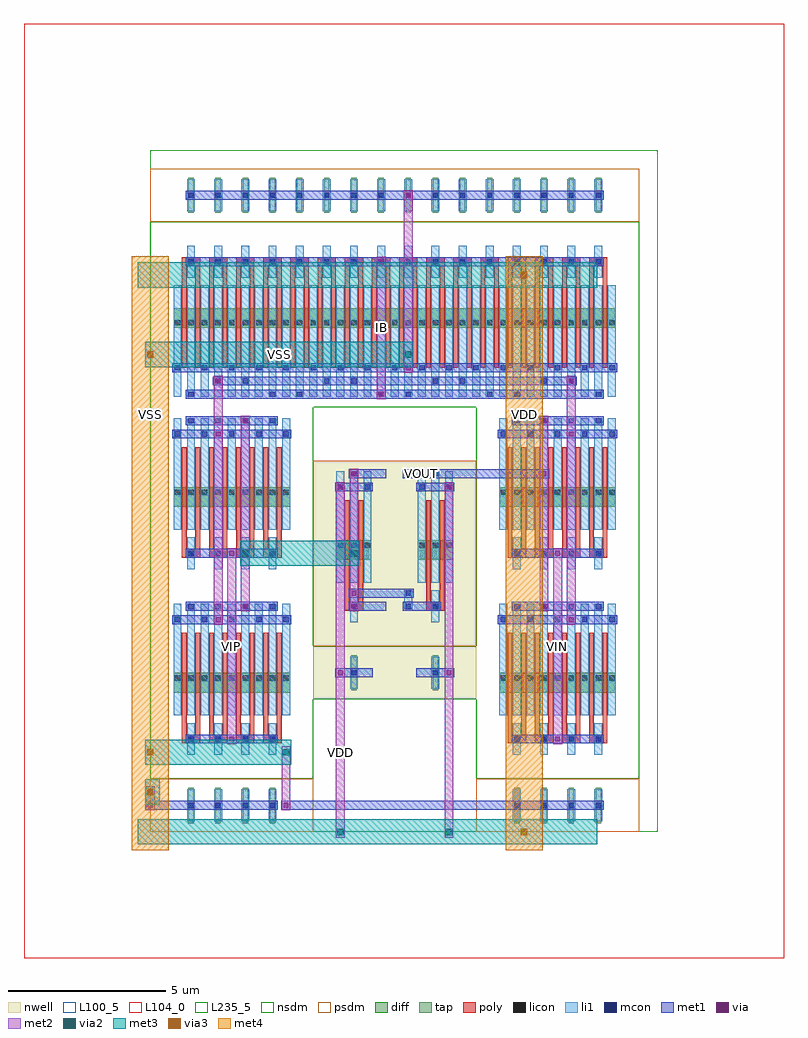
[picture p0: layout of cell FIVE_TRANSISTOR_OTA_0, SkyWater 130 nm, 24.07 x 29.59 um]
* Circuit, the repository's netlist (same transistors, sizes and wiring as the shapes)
* NGSPICE file created from FIVE_TRANSISTOR_OTA_0.ext - technology: sky130A

.subckt DCL_PMOS_S_8161858_X1_Y1_1774869053 a_200_252# w_0_0#
X0 a_200_252# a_200_252# w_0_0# w_0_0# sky130_fd_pr__pfet_01v8 ad=0.0882 pd=0.91 as=0.16695 ps=1.79 w=0.63 l=0.15 M=2
.ends

.subckt SCM_NMOS_1433580_X8_Y1_1774869056 a_147_504# a_200_252# a_402_504#
X0 a_147_504# a_200_252# a_402_504# a_147_504# sky130_fd_pr__nfet_01v8 ad=0.0882 pd=0.91 as=0.0882 ps=0.91 w=0.63 l=0.15 M=16
X1 a_200_252# a_200_252# a_147_504# a_147_504# sky130_fd_pr__nfet_01v8 ad=0.0882 pd=0.91 as=0.16695 ps=1.79 w=0.63 l=0.15 M=16
.ends

.subckt PMOS_S_96204883_X1_Y1_1774869055 a_200_252# w_0_0# a_230_504#
X0 a_230_504# a_200_252# w_0_0# w_0_0# sky130_fd_pr__pfet_01v8 ad=0.0882 pd=0.91 as=0.16695 ps=1.79 w=0.63 l=0.15 M=2
.ends

.subckt NMOS_4T_7455775_X4_Y2_1774869054 a_147_504# a_200_252# a_230_504# a_241_2408#
X0 a_230_504# a_200_252# a_147_504# a_241_2408# sky130_fd_pr__nfet_01v8 ad=0.0882 pd=0.91 as=0.16695 ps=1.79 w=0.63 l=0.15 M=16
.ends

.subckt FIVE_TRANSISTOR_OTA_0 IB VOUT VIP VIN VSS VDD
XDCL_PMOS_S_8161858_X1_Y1_1774869053_0 m2_574_1727# VDD DCL_PMOS_S_8161858_X1_Y1_1774869053
XSCM_NMOS_1433580_X8_Y1_1774869056_0 VSS IB m1_398_2828# SCM_NMOS_1433580_X8_Y1_1774869056
XPMOS_S_96204883_X1_Y1_1774869055_0 m2_574_1727# VDD VOUT PMOS_S_96204883_X1_Y1_1774869055
XNMOS_4T_7455775_X4_Y2_1774869054_0 m1_398_2828# VIN VOUT VSS NMOS_4T_7455775_X4_Y2_1774869054
XNMOS_4T_7455775_X4_Y2_1774869054_1 m1_398_2828# VIP m2_574_1727# VSS NMOS_4T_7455775_X4_Y2_1774869054
.ends

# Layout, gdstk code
from math import pi, radians
import gdstk
lib = gdstk.Library(unit=1e-6, precision=1e-09)
def R(c, l, rs):  # rectangles x0, y0, x1, y1
    for r in rs: c.add(gdstk.rectangle(r[:2], r[2:], *l))
def A(c, l, x, y, w, h, nx, ny, dx, dy):  # array of equal rectangles
    R(c, l, [(x+i*dx, y+j*dy, x+i*dx+w, y+j*dy+h) for i in range(nx) for j in range(ny)])
def P(c, l, *ps):  # polygons
    for p in ps: c.add(gdstk.Polygon(p, *l))
nwell = (64, 20)
diff = (65, 20)
tap = (65, 44)
poly = (66, 20)
licon = (66, 44)
li1 = (67, 20)
mcon = (67, 44)
met1 = (68, 20)
via = (68, 44)
met2 = (69, 20)
via2 = (69, 44)
met3 = (70, 20)
via3 = (70, 44)
met4 = (71, 20)
nsdm = (93, 44)
psdm = (94, 20)
L100_5 = (100, 5)
L104_0 = (104, 0)
L235_5 = (235, 5)

scm_nmos_1433580_x8_y1_1 = lib.new_cell('SCM_NMOS_1433580_X8_Y1_1774869056')
R(scm_nmos_1433580_x8_y1_1, diff, [(0.735,2.52,14.745,3.15)])
A(scm_nmos_1433580_x8_y1_1, tap, 1.205, 6.16, 0.17, 1.12, 16, 1, 0.86, 0)
A(scm_nmos_1433580_x8_y1_1, poly, 1, 1.26, 0.15, 3.36, 32, 1, 0.43, 0)
A(scm_nmos_1433580_x8_y1_1, poly, 1, 4.485, 0.58, 0.27, 16, 1, 0.86, 0)
A(scm_nmos_1433580_x8_y1_1, licon, 0.775, 2.6, 0.17, 0.17, 3, 1, 0.43, 0)
A(scm_nmos_1433580_x8_y1_1, licon, 1.635, 2.6, 0.17, 0.17, 3, 1, 0.43, 0)
A(scm_nmos_1433580_x8_y1_1, licon, 2.495, 2.6, 0.17, 0.17, 3, 1, 0.43, 0)
A(scm_nmos_1433580_x8_y1_1, licon, 3.355, 2.6, 0.17, 0.17, 3, 1, 0.43, 0)
A(scm_nmos_1433580_x8_y1_1, licon, 4.215, 2.6, 0.17, 0.17, 3, 1, 0.43, 0)
A(scm_nmos_1433580_x8_y1_1, licon, 5.075, 2.6, 0.17, 0.17, 3, 1, 0.43, 0)
A(scm_nmos_1433580_x8_y1_1, licon, 5.935, 2.6, 0.17, 0.17, 3, 1, 0.43, 0)
A(scm_nmos_1433580_x8_y1_1, licon, 6.795, 2.6, 0.17, 0.17, 3, 1, 0.43, 0)
A(scm_nmos_1433580_x8_y1_1, licon, 7.655, 2.6, 0.17, 0.17, 3, 1, 0.43, 0)
A(scm_nmos_1433580_x8_y1_1, licon, 8.515, 2.6, 0.17, 0.17, 3, 1, 0.43, 0)
A(scm_nmos_1433580_x8_y1_1, licon, 9.375, 2.6, 0.17, 0.17, 3, 1, 0.43, 0)
A(scm_nmos_1433580_x8_y1_1, licon, 10.235, 2.6, 0.17, 0.17, 3, 1, 0.43, 0)
A(scm_nmos_1433580_x8_y1_1, licon, 11.095, 2.6, 0.17, 0.17, 3, 1, 0.43, 0)
A(scm_nmos_1433580_x8_y1_1, licon, 11.955, 2.6, 0.17, 0.17, 3, 1, 0.43, 0)
A(scm_nmos_1433580_x8_y1_1, licon, 12.815, 2.6, 0.17, 0.17, 3, 1, 0.43, 0)
A(scm_nmos_1433580_x8_y1_1, licon, 13.675, 2.6, 0.17, 0.17, 3, 1, 0.43, 0)
A(scm_nmos_1433580_x8_y1_1, licon, 1.205, 4.535, 0.17, 0.17, 16, 2, 0.86, 2.1)
A(scm_nmos_1433580_x8_y1_1, li1, 0.735, 0.335, 0.25, 3.53, 33, 1, 0.43, 0)
A(scm_nmos_1433580_x8_y1_1, li1, 1.165, 4.115, 0.25, 1.01, 16, 2, 0.86, 2.1)
A(scm_nmos_1433580_x8_y1_1, mcon, 0.775, 1.175, 0.17, 0.17, 17, 1, 0.86, 0)
A(scm_nmos_1433580_x8_y1_1, mcon, 1.205, 4.535, 0.17, 0.17, 16, 2, 0.86, 2.1)
R(scm_nmos_1433580_x8_y1_1, mcon, [(1.205,0.335,1.375,0.505), (3.785,0.335,3.955,0.505), (4.645,0.335,4.815,0.505), (7.225,0.335,7.395,0.505), (8.085,0.335,8.255,0.505), (10.665,0.335,10.835,0.505), (11.525,0.335,11.695,0.505), (14.105,0.335,14.275,0.505), (2.065,0.755,2.235,0.925), (2.925,0.755,3.095,0.925), (5.505,0.755,5.675,0.925), (6.365,0.755,6.535,0.925), (8.945,0.755,9.115,0.925), (9.805,0.755,9.975,0.925), (12.385,0.755,12.555,0.925), (13.245,0.755,13.415,0.925)])
R(scm_nmos_1433580_x8_y1_1, met1, [(1.12,0.28,14.36,0.56), (1.98,0.7,13.5,0.98), (0.69,1.12,14.79,1.4), (1.12,4.48,14.36,4.76), (1.12,6.58,14.36,6.86)])
R(scm_nmos_1433580_x8_y1_1, via, [(7.235,0.345,7.385,0.495), (8.095,1.185,8.245,1.335), (7.235,4.545,7.385,4.695), (8.095,6.645,8.245,6.795)])
R(scm_nmos_1433580_x8_y1_1, met2, [(7.17,0.26,7.45,4.78), (8.03,1.1,8.31,6.88)])
R(scm_nmos_1433580_x8_y1_1, nsdm, [(0,0,15.48,5.88)])
R(scm_nmos_1433580_x8_y1_1, psdm, [(0,5.88,15.48,7.56)])
R(scm_nmos_1433580_x8_y1_1, L100_5, [(0,0,15.48,7.56)])

dcl_pmos_s_8161858_x1_y1 = lib.new_cell('DCL_PMOS_S_8161858_X1_Y1_1774869053')
R(dcl_pmos_s_8161858_x1_y1, nwell, [(0,0,2.58,7.56)])
R(dcl_pmos_s_8161858_x1_y1, diff, [(0.735,2.52,1.845,3.15)])
R(dcl_pmos_s_8161858_x1_y1, tap, [(1.205,6.16,1.375,7.28)])
R(dcl_pmos_s_8161858_x1_y1, poly, [(1,1.26,1.15,4.62), (1.43,1.26,1.58,4.62), (1,4.485,1.58,4.755)])
A(dcl_pmos_s_8161858_x1_y1, licon, 0.775, 2.6, 0.17, 0.17, 3, 1, 0.43, 0)
R(dcl_pmos_s_8161858_x1_y1, licon, [(1.205,4.535,1.375,4.705), (1.205,6.635,1.375,6.805)])
A(dcl_pmos_s_8161858_x1_y1, li1, 0.735, 0.335, 0.25, 3.53, 3, 1, 0.43, 0)
R(dcl_pmos_s_8161858_x1_y1, li1, [(1.165,4.115,1.415,5.125), (1.165,6.215,1.415,7.225)])
R(dcl_pmos_s_8161858_x1_y1, mcon, [(1.205,0.335,1.375,0.505), (0.775,0.755,0.945,0.925), (1.635,0.755,1.805,0.925), (1.205,4.535,1.375,4.705), (1.205,6.635,1.375,6.805)])
R(dcl_pmos_s_8161858_x1_y1, met1, [(0.26,0.28,1.46,0.56), (0.69,0.7,1.89,0.98), (0.26,4.48,1.46,4.76), (0.69,6.58,1.89,6.86)])
R(dcl_pmos_s_8161858_x1_y1, via, [(1.215,0.345,1.365,0.495), (1.645,0.765,1.795,0.915), (1.215,4.545,1.365,4.695), (1.645,6.645,1.795,6.795)])
R(dcl_pmos_s_8161858_x1_y1, met2, [(1.15,0.26,1.43,4.78), (1.58,0.68,1.86,6.88)])
R(dcl_pmos_s_8161858_x1_y1, nsdm, [(0,5.88,2.58,7.56)])
R(dcl_pmos_s_8161858_x1_y1, psdm, [(0,0,2.58,5.88)])
R(dcl_pmos_s_8161858_x1_y1, L100_5, [(0,0,2.58,7.56)])

pmos_s_96204883_x1_y1_17 = lib.new_cell('PMOS_S_96204883_X1_Y1_1774869055')
R(pmos_s_96204883_x1_y1_17, nwell, [(0,0,2.58,7.56)])
R(pmos_s_96204883_x1_y1_17, diff, [(0.735,2.52,1.845,3.15)])
R(pmos_s_96204883_x1_y1_17, tap, [(1.205,6.16,1.375,7.28)])
R(pmos_s_96204883_x1_y1_17, poly, [(1,1.26,1.15,4.62), (1.43,1.26,1.58,4.62), (1,4.485,1.58,4.755)])
A(pmos_s_96204883_x1_y1_17, licon, 0.775, 2.6, 0.17, 0.17, 3, 1, 0.43, 0)
R(pmos_s_96204883_x1_y1_17, licon, [(1.205,4.535,1.375,4.705), (1.205,6.635,1.375,6.805)])
A(pmos_s_96204883_x1_y1_17, li1, 0.735, 0.335, 0.25, 3.53, 3, 1, 0.43, 0)
R(pmos_s_96204883_x1_y1_17, li1, [(1.165,4.115,1.415,5.125), (1.165,6.215,1.415,7.225)])
R(pmos_s_96204883_x1_y1_17, mcon, [(1.205,0.335,1.375,0.505), (0.775,0.755,0.945,0.925), (1.635,0.755,1.805,0.925), (1.205,4.535,1.375,4.705), (1.205,6.635,1.375,6.805)])
R(pmos_s_96204883_x1_y1_17, met1, [(0.26,0.28,1.46,0.56), (0.69,0.7,1.89,0.98), (0.26,4.48,1.46,4.76), (0.69,6.58,1.89,6.86)])
R(pmos_s_96204883_x1_y1_17, via, [(1.645,0.765,1.795,0.915), (1.645,6.645,1.795,6.795)])
R(pmos_s_96204883_x1_y1_17, met2, [(1.58,0.68,1.86,6.88)])
R(pmos_s_96204883_x1_y1_17, nsdm, [(0,5.88,2.58,7.56)])
R(pmos_s_96204883_x1_y1_17, psdm, [(0,0,2.58,5.88)])
R(pmos_s_96204883_x1_y1_17, L100_5, [(0,0,2.58,7.56)])

nmos_4t_7455775_x4_y2_17 = lib.new_cell('NMOS_4T_7455775_X4_Y2_1774869054')
R(nmos_4t_7455775_x4_y2_17, diff, [(0.735,2.52,4.425,3.15), (0.735,8.4,4.425,9.03)])
A(nmos_4t_7455775_x4_y2_17, tap, 1.205, 12.04, 0.17, 1.12, 4, 1, 0.86, 0)
A(nmos_4t_7455775_x4_y2_17, poly, 1, 1.26, 0.15, 3.36, 8, 2, 0.43, 5.88)
A(nmos_4t_7455775_x4_y2_17, poly, 1, 4.485, 0.58, 0.27, 4, 2, 0.86, 5.88)
A(nmos_4t_7455775_x4_y2_17, licon, 0.775, 2.6, 0.17, 0.17, 3, 2, 0.43, 5.88)
A(nmos_4t_7455775_x4_y2_17, licon, 1.635, 2.6, 0.17, 0.17, 3, 2, 0.43, 5.88)
A(nmos_4t_7455775_x4_y2_17, licon, 2.495, 2.6, 0.17, 0.17, 3, 2, 0.43, 5.88)
A(nmos_4t_7455775_x4_y2_17, licon, 3.355, 2.6, 0.17, 0.17, 3, 2, 0.43, 5.88)
A(nmos_4t_7455775_x4_y2_17, licon, 1.205, 4.535, 0.17, 0.17, 4, 2, 0.86, 5.88)
R(nmos_4t_7455775_x4_y2_17, licon, [(1.205,12.515,1.375,12.685), (1.205,12.515,1.375,12.685), (2.065,12.515,2.235,12.685), (2.065,12.515,2.235,12.685), (2.925,12.515,3.095,12.685), (2.925,12.515,3.095,12.685), (3.785,12.515,3.955,12.685), (3.785,12.515,3.955,12.685)])
A(nmos_4t_7455775_x4_y2_17, li1, 0.735, 0.335, 0.25, 3.53, 9, 2, 0.43, 5.88)
A(nmos_4t_7455775_x4_y2_17, li1, 1.165, 4.115, 0.25, 1.01, 4, 2, 0.86, 5.88)
A(nmos_4t_7455775_x4_y2_17, li1, 1.165, 12.095, 0.25, 1.01, 4, 1, 0.86, 0)
A(nmos_4t_7455775_x4_y2_17, mcon, 1.205, 0.335, 0.17, 0.17, 4, 2, 0.86, 4.2)
A(nmos_4t_7455775_x4_y2_17, mcon, 0.775, 0.755, 0.17, 0.17, 5, 2, 0.86, 5.88)
A(nmos_4t_7455775_x4_y2_17, mcon, 1.205, 6.215, 0.17, 0.17, 4, 2, 0.86, 4.2)
A(nmos_4t_7455775_x4_y2_17, mcon, 1.205, 12.515, 0.17, 0.17, 4, 1, 0.86, 0)
R(nmos_4t_7455775_x4_y2_17, met1, [(1.12,0.28,4.04,0.56), (0.69,0.7,4.47,0.98), (1.12,4.48,4.04,4.76), (1.12,6.16,4.04,6.44), (0.69,6.58,4.47,6.86), (1.12,10.36,4.04,10.64), (1.12,12.46,4.04,12.74)])
R(nmos_4t_7455775_x4_y2_17, via, [(2.075,0.345,2.225,0.495), (2.935,0.765,3.085,0.915), (2.505,4.545,2.655,4.695), (2.075,6.225,2.225,6.375), (2.935,6.645,3.085,6.795), (2.505,10.425,2.655,10.575)])
R(nmos_4t_7455775_x4_y2_17, met2, [(2.01,0.26,2.29,6.46), (2.87,0.68,3.15,6.88), (2.44,4.46,2.72,10.66)])
R(nmos_4t_7455775_x4_y2_17, nsdm, [(0,0,5.16,11.76)])
R(nmos_4t_7455775_x4_y2_17, psdm, [(0,11.76,5.16,13.44)])
R(nmos_4t_7455775_x4_y2_17, L100_5, [(0,0,5.16,13.44)])

five_transistor_ota_0 = lib.new_cell('FIVE_TRANSISTOR_OTA_0')
R(five_transistor_ota_0, li1, [(8.045,7.055,8.295,7.225), (8.045,7.055,8.295,7.225), (8.045,7.14,8.295,7.56), (8.045,7.475,8.295,7.645), (8.045,7.475,8.295,7.645)])
R(five_transistor_ota_0, mcon, [(8.085,7.055,8.255,7.225), (8.085,7.055,8.255,7.225), (8.085,7.475,8.255,7.645), (8.085,7.475,8.255,7.645)])
R(five_transistor_ota_0, met1, [(-0.16,0.7,0.16,0.98), (-0.16,0.7,0.16,0.98), (-0.16,0.7,0.16,0.98), (0,0.7,1.29,0.98), (4.14,0.7,4.46,0.98), (4.14,0.7,4.46,0.98), (4.3,0.7,11.61,0.98), (8,7,8.34,7.28), (8,7,8.34,7.28), (6.29,7.42,6.61,7.7), (6.29,7.42,6.61,7.7), (6.45,7.42,8.17,7.7), (8,7.42,8.34,7.7), (8,7.42,8.34,7.7), (9.03,11.2,12.47,11.48), (12.31,11.2,12.63,11.48), (12.31,11.2,12.63,11.48), (1.99,14.14,2.31,14.42), (1.99,14.14,2.31,14.42), (1.99,14.14,2.31,14.42), (1.99,14.14,2.31,14.42), (13.17,14.14,13.49,14.42), (13.17,14.14,13.49,14.42)])
P(five_transistor_ota_0, met1, [(0,0),(0,0),(0,0),(0,0)],
  [(0,0),(0,0),(0,0),(0,0)],
  [(0,0),(0,0),(0,0),(0,0)],
  [(0,0),(0,0),(0,0),(0,0)],
  [(0,0),(0,0),(0,0),(0,0)],
  [(0,0),(0,0),(0,0),(0,0)])
R(five_transistor_ota_0, via, [(-0.075,0.765,0.075,0.915), (-0.075,0.765,0.075,0.915), (-0.075,0.765,0.075,0.915), (4.225,0.765,4.375,0.915), (4.225,0.765,4.375,0.915), (6.375,7.485,6.525,7.635), (6.375,7.485,6.525,7.635), (12.395,11.265,12.545,11.415), (12.395,11.265,12.545,11.415), (2.075,14.205,2.225,14.355), (2.075,14.205,2.225,14.355), (2.075,14.205,2.225,14.355), (2.075,14.205,2.225,14.355), (13.255,14.205,13.405,14.355), (13.255,14.205,13.405,14.355)])
R(five_transistor_ota_0, met2, [(5.88,-0.185,6.16,0.185), (5.88,-0.185,6.16,0.185), (5.88,-0.185,6.16,0.185), (9.32,-0.185,9.6,0.185), (9.32,-0.185,9.6,0.185), (5.88,0,6.16,5.04), (9.32,0,9.6,5.04), (-0.14,0.68,0.14,1), (-0.14,0.68,0.14,1), (-0.14,0.68,0.14,1), (4.16,0.68,4.44,1), (4.16,0.68,4.44,1), (-0.14,0.84,0.14,1.26), (4.16,0.84,4.44,2.52), (-0.14,1.075,0.14,1.445), (-0.14,1.075,0.14,1.445), (-0.14,1.075,0.14,1.445), (4.16,2.335,4.44,2.705), (4.16,2.335,4.44,2.705), (6.31,7.4,6.59,7.72), (6.31,7.4,6.59,7.72), (2.87,8.635,3.15,9.005), (2.87,8.635,3.15,9.005), (2.87,8.635,3.15,9.005), (2.87,8.635,3.15,9.005), (6.31,8.635,6.59,9.005), (6.31,8.635,6.59,9.005), (6.31,8.635,6.59,9.005), (6.31,8.635,6.59,9.005), (12.33,11.18,12.61,11.5), (12.33,11.18,12.61,11.5), (2.01,12.6,2.29,14.28), (13.19,12.6,13.47,14.28), (2.01,14.12,2.29,14.44), (2.01,14.12,2.29,14.44), (2.01,14.12,2.29,14.44), (2.01,14.12,2.29,14.44), (13.19,14.12,13.47,14.44), (13.19,14.12,13.47,14.44), (8.03,14.935,8.31,15.305), (8.03,14.935,8.31,15.305), (8.03,14.935,8.31,15.305), (8.03,14.935,8.31,15.305)])
P(five_transistor_ota_0, met2, [(0,0),(0,0),(0,0),(0,0)],
  [(0,0),(0,0),(0,0),(0,0)],
  [(0,0),(0,0),(0,0),(0,0)],
  [(0,0),(0,0),(0,0),(0,0)],
  [(0,0),(0,0),(0,0),(0,0)],
  [(0,0),(0,0),(0,0),(0,0)],
  [(0,0),(0,0),(0,0),(0,0)],
  [(0,0),(0,0),(0,0),(0,0)],
  [(0,0),(0,0),(0,0),(0,0)],
  [(0,0),(0,0),(0,0),(0,0)],
  [(0,0),(0,0),(0,0),(0,0)],
  [(0,0),(0,0),(0,0),(0,0)],
  [(0,0),(0,0),(0,0),(0,0)],
  [(0,0),(0,0),(0,0),(0,0)])
R(five_transistor_ota_0, via2, [(5.92,-0.1,6.12,0.1), (5.92,-0.1,6.12,0.1), (5.92,-0.1,6.12,0.1), (9.36,-0.1,9.56,0.1), (9.36,-0.1,9.56,0.1), (-0.1,1.16,0.1,1.36), (-0.1,1.16,0.1,1.36), (-0.1,1.16,0.1,1.36), (4.2,2.42,4.4,2.62), (4.2,2.42,4.4,2.62), (2.91,8.72,3.11,8.92), (2.91,8.72,3.11,8.92), (2.91,8.72,3.11,8.92), (2.91,8.72,3.11,8.92), (6.35,8.72,6.55,8.92), (6.35,8.72,6.55,8.92), (6.35,8.72,6.55,8.92), (6.35,8.72,6.55,8.92), (8.07,15.02,8.27,15.22), (8.07,15.02,8.27,15.22), (8.07,15.02,8.27,15.22), (8.07,15.02,8.27,15.22)])
A(five_transistor_ota_0, met3, -0.4, -0.4, 4.24, 0.8, 3, 2, 3.44, 17.64)
R(five_transistor_ota_0, met3, [(5.855,-0.4,6.185,0.4), (5.855,-0.4,6.185,0.4), (5.855,-0.4,6.185,0.4), (9.295,-0.4,9.625,0.4), (9.295,-0.4,9.625,0.4), (9.92,-0.4,12.24,0.4), (11.44,-0.4,14.16,0.4), (11.675,-0.4,12.005,0.4), (-0.165,0.86,0.165,1.66), (-0.165,0.86,0.165,1.66), (-0.165,0.86,0.165,1.66), (-0.165,0.86,0.165,1.66), (-0.165,0.86,0.165,1.66), (-0.165,0.86,0.165,1.66), (0,0.86,0.3,1.66), (-0.165,2.12,0.165,2.92), (-0.165,2.12,0.165,2.92), (0,2.12,4.3,2.92), (4.135,2.12,4.465,2.92), (4.135,2.12,4.465,2.92), (2.845,8.42,3.175,9.22), (2.845,8.42,3.175,9.22), (2.845,8.42,3.175,9.22), (2.845,8.42,3.175,9.22), (3.01,8.42,6.45,9.22), (6.285,8.42,6.615,9.22), (6.285,8.42,6.615,9.22), (6.285,8.42,6.615,9.22), (6.285,8.42,6.615,9.22), (-0.165,14.72,0.165,15.52), (-0.165,14.72,0.165,15.52), (-0.165,14.72,0.165,15.52), (-0.165,14.72,0.165,15.52), (0,14.72,8.17,15.52), (8.005,14.72,8.335,15.52), (8.005,14.72,8.335,15.52), (8.005,14.72,8.335,15.52), (8.005,14.72,8.335,15.52), (9.92,17.24,12.24,18.04), (11.44,17.24,14.16,18.04), (11.675,17.24,12.005,18.04)])
R(five_transistor_ota_0, via3, [(11.74,-0.1,11.94,0.1), (-0.1,1.16,0.1,1.36), (-0.1,1.16,0.1,1.36), (-0.1,1.16,0.1,1.36), (-0.1,2.42,0.1,2.62), (-0.1,2.42,0.1,2.62), (-0.1,15.02,0.1,15.22), (-0.1,15.02,0.1,15.22), (-0.1,15.02,0.1,15.22), (-0.1,15.02,0.1,15.22), (11.74,17.54,11.94,17.74)])
R(five_transistor_ota_0, met4, [(-0.59,-0.59,0.59,9.41), (11.25,-0.59,12.43,9.41), (11.25,-0.165,12.43,0.165), (-0.59,1.095,0.59,1.425), (-0.59,1.095,0.59,1.425), (-0.59,1.095,0.59,1.425), (-0.59,2.355,0.59,2.685), (-0.59,2.355,0.59,2.685), (-0.59,8.23,0.59,18.23), (11.25,8.23,12.43,18.23), (-0.59,14.955,0.59,15.285), (-0.59,14.955,0.59,15.285), (-0.59,14.955,0.59,15.285), (-0.59,14.955,0.59,15.285), (11.25,17.475,12.43,17.805)])
R(five_transistor_ota_0, L104_0, [(-4,-4,20.07,25.59)])
R(five_transistor_ota_0, L235_5, [(0,0,16.07,21.59)])
five_transistor_ota_0.add(gdstk.Reference(scm_nmos_1433580_x8_y1_1, (0,13.44)))
five_transistor_ota_0.add(gdstk.Reference(dcl_pmos_s_8161858_x1_y1, (7.74,11.76), rotation=pi))
five_transistor_ota_0.add(gdstk.Reference(pmos_s_96204883_x1_y1_17, (7.74,11.76), x_reflection=True))
five_transistor_ota_0.add(gdstk.Reference(nmos_4t_7455775_x4_y2_17, (5.16,13.44), rotation=pi))
five_transistor_ota_0.add(gdstk.Reference(nmos_4t_7455775_x4_y2_17, (10.32,13.44), x_reflection=True))
five_transistor_ota_0.add(gdstk.Label('IB', (7.31,15.96), layer=69, texttype=5))
five_transistor_ota_0.add(gdstk.Label('VOUT', (8.6,11.34), layer=68, texttype=5))
five_transistor_ota_0.add(gdstk.Label('VIP', (2.58,5.88), layer=69, texttype=5))
five_transistor_ota_0.add(gdstk.Label('VIN', (12.9,5.88), layer=69, texttype=5))
five_transistor_ota_0.add(gdstk.Label('VSS', (0,13.23), layer=71, texttype=5))
five_transistor_ota_0.add(gdstk.Label('VSS', (4.085,15.12), layer=70, texttype=5))
five_transistor_ota_0.add(gdstk.Label('VSS', (0,13.23), layer=71, texttype=5))
five_transistor_ota_0.add(gdstk.Label('VSS', (0,13.23), layer=71, texttype=5))
five_transistor_ota_0.add(gdstk.Label('VSS', (0,13.23), layer=71, texttype=5))
five_transistor_ota_0.add(gdstk.Label('VSS', (0,13.23), layer=71, texttype=5))
five_transistor_ota_0.add(gdstk.Label('VSS', (0,13.23), layer=71, texttype=5))
five_transistor_ota_0.add(gdstk.Label('VSS', (0,13.23), layer=71, texttype=5))
five_transistor_ota_0.add(gdstk.Label('VSS', (0,13.23), layer=71, texttype=5))
five_transistor_ota_0.add(gdstk.Label('VSS', (0,13.23), layer=71, texttype=5))
five_transistor_ota_0.add(gdstk.Label('VSS', (0,13.23), layer=71, texttype=5))
five_transistor_ota_0.add(gdstk.Label('VSS', (0,13.23), layer=71, texttype=5))
five_transistor_ota_0.add(gdstk.Label('VDD', (6.02,2.52), layer=69, texttype=5))
five_transistor_ota_0.add(gdstk.Label('VDD', (11.84,13.23), layer=71, texttype=5))
five_transistor_ota_0.add(gdstk.Label('VDD', (11.84,13.23), layer=71, texttype=5))
five_transistor_ota_0.add(gdstk.Label('VDD', (11.84,13.23), layer=71, texttype=5))
five_transistor_ota_0.add(gdstk.Label('VDD', (11.84,13.23), layer=71, texttype=5))

lib.write_gds('FIVE_TRANSISTOR_OTA_0.gds')
